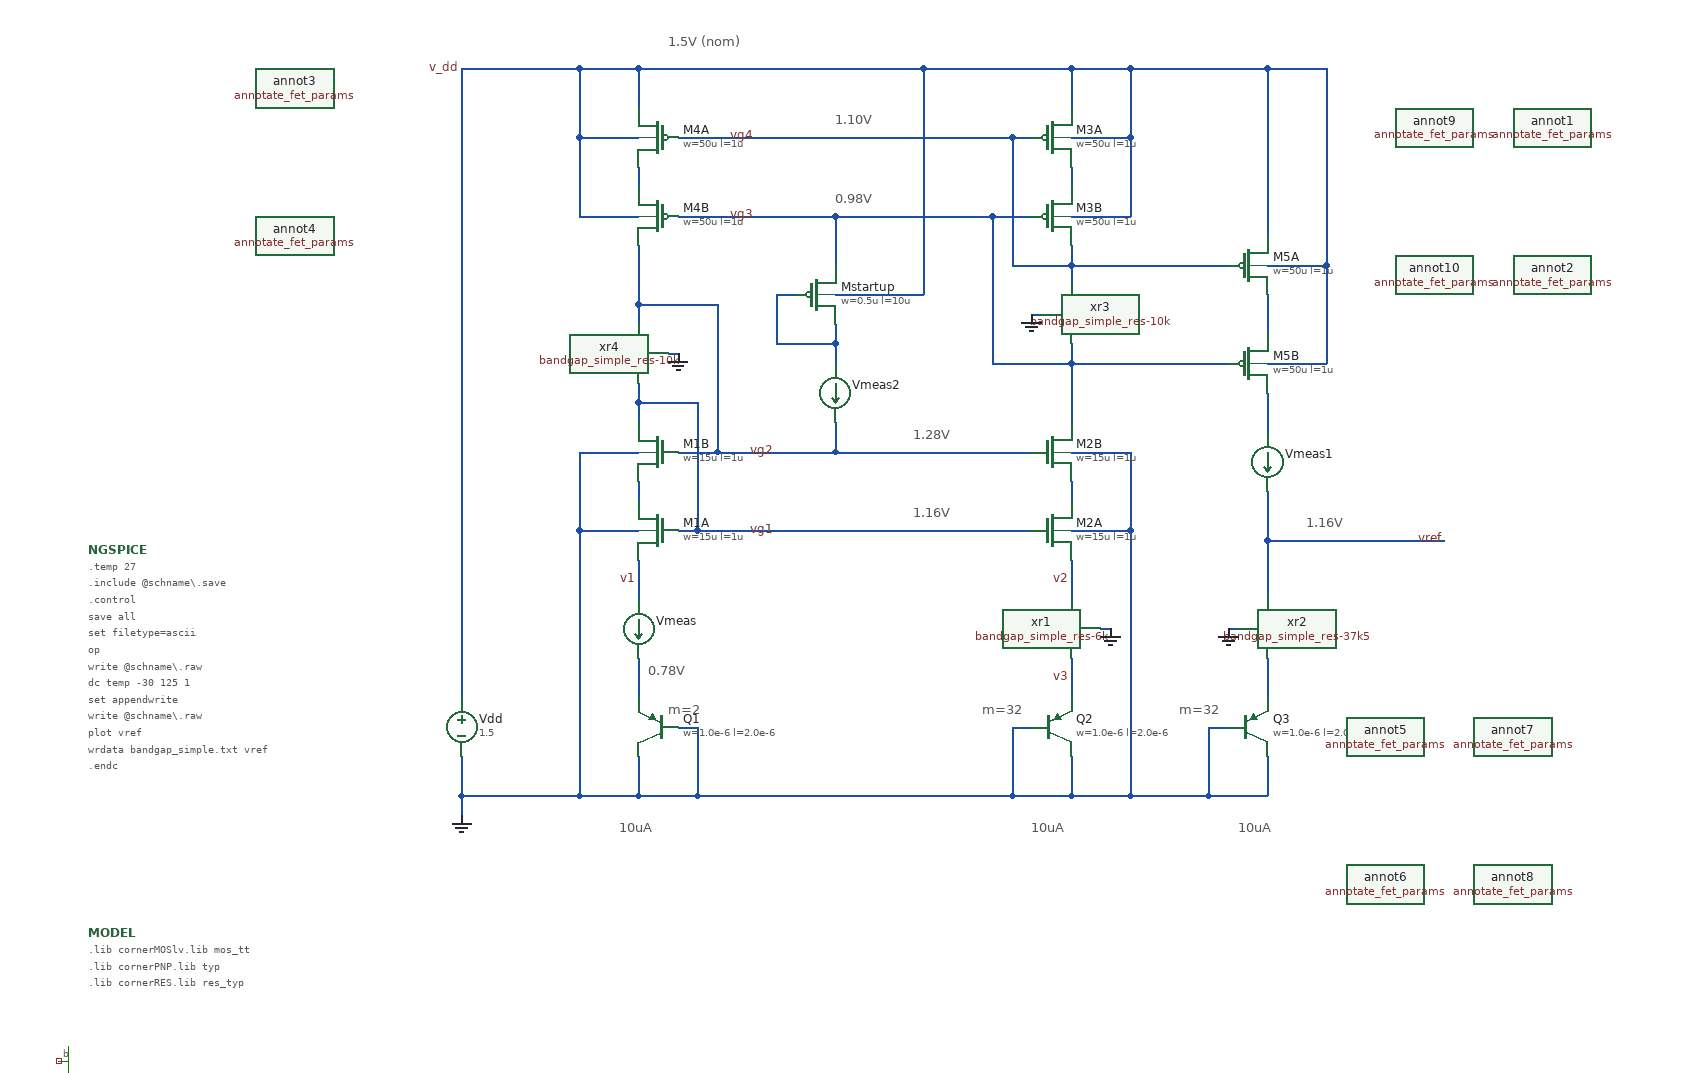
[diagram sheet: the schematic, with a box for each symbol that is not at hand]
v {xschem version=3.4.8RC file_version=1.3}
G {}
K {}
V {}
S {}
F {}
E {}
L 4 -20 -45 -20 -15 {}
L 4 -30 -30 -20 -30 {}
B 5 -32.5 -32.5 -27.5 -27.5 {name=b dir=inout}
T {m=32} 910 -400 0 0 0.4 0.4 {}
T {10uA} 540 -280 0 0 0.4 0.4 {}
T {10uA} 960 -280 0 0 0.4 0.4 {}
T {10uA} 1170 -280 0 0 0.4 0.4 {}
T {m=2} 590 -400 0 0 0.4 0.4 {}
T {m=32} 1110 -400 0 0 0.4 0.4 {}
T {1.16V} 1240 -590 0 0 0.4 0.4 {}
T {1.16V} 840 -600 0 0 0.4 0.4 {}
T {1.28V} 840 -680 0 0 0.4 0.4 {}
T {1.10V} 760 -1000 0 0 0.4 0.4 {}
T {0.98V} 760 -920 0 0 0.4 0.4 {}
T {0.78V} 570 -440 0 0 0.4 0.4 {}
T {1.5V (nom)} 590 -1080 0 0 0.4 0.4 {}
T {b} -25 -49 0 1 0.2 0.2 {}
N 380 -300 380 -280 {
lab=GND}
N 380 -340 380 -300 {
lab=GND}
N 1000 -340 1000 -300 {lab=GND}
N 560 -340 560 -300 {lab=GND}
N 940 -370 960 -370 {lab=GND}
N 940 -370 940 -300 {lab=GND}
N 600 -370 620 -370 {lab=GND}
N 620 -370 620 -300 {lab=GND}
N 560 -300 620 -300 {
lab=GND}
N 1000 -440 1000 -400 {lab=v3}
N 560 -1040 560 -1000 {lab=v_dd}
N 850 -1040 1000 -1040 {lab=v_dd}
N 1000 -1040 1000 -1000 {lab=v_dd}
N 500 -1040 560 -1040 {lab=v_dd}
N 940 -970 960 -970 {lab=vg4}
N 600 -570 620 -570 {lab=vg1}
N 500 -970 560 -970 {lab=v_dd}
N 500 -1040 500 -970 {lab=v_dd}
N 380 -1040 500 -1040 {lab=v_dd}
N 1000 -970 1060 -970 {lab=v_dd}
N 1060 -1040 1060 -970 {lab=v_dd}
N 1000 -1040 1060 -1040 {lab=v_dd}
N 500 -570 560 -570 {lab=GND}
N 500 -300 560 -300 {
lab=GND}
N 1000 -570 1060 -570 {lab=GND}
N 1060 -300 1140 -300 {lab=GND}
N 1140 -300 1200 -300 {
lab=GND}
N 1200 -340 1200 -300 {lab=GND}
N 1140 -370 1160 -370 {lab=GND}
N 1140 -370 1140 -300 {lab=GND}
N 1200 -440 1200 -400 {lab=#net1}
N 1060 -1040 1200 -1040 {lab=v_dd}
N 1200 -560 1200 -500 {lab=vref}
N 1200 -1040 1260 -1040 {lab=v_dd}
N 1200 -560 1380 -560 {lab=vref}
N 560 -440 560 -400 {lab=#net2}
N 1200 -610 1200 -560 {lab=vref}
N 1000 -620 1000 -600 {lab=#net3}
N 1000 -650 1060 -650 {lab=GND}
N 1060 -650 1060 -570 {lab=GND}
N 560 -620 560 -600 {lab=#net4}
N 500 -650 560 -650 {lab=GND}
N 500 -650 500 -570 {lab=GND}
N 560 -700 620 -700 {lab=vg1}
N 560 -700 560 -680 {lab=vg1}
N 560 -720 560 -700 {lab=vg1}
N 620 -700 620 -570 {lab=vg1}
N 640 -800 640 -650 {lab=vg2}
N 600 -650 640 -650 {lab=vg2}
N 560 -800 640 -800 {lab=vg2}
N 560 -800 560 -780 {lab=vg2}
N 560 -860 560 -800 {lab=vg2}
N 560 -940 560 -920 {lab=#net5}
N 920 -890 960 -890 {lab=vg3}
N 1000 -940 1000 -920 {lab=#net6}
N 1000 -890 1060 -890 {lab=v_dd}
N 1060 -970 1060 -890 {lab=v_dd}
N 500 -890 560 -890 {lab=v_dd}
N 500 -970 500 -890 {lab=v_dd}
N 940 -840 1000 -840 {lab=vg4}
N 920 -890 920 -740 {lab=vg3}
N 1000 -760 1000 -740 {lab=vg3}
N 1000 -740 1160 -740 {lab=vg3}
N 1000 -740 1000 -680 {lab=vg3}
N 940 -970 940 -840 {lab=vg4}
N 1000 -860 1000 -840 {lab=vg4}
N 1000 -840 1160 -840 {lab=vg4}
N 1000 -840 1000 -820 {lab=vg4}
N 380 -1040 380 -400 {lab=v_dd}
N 560 -540 560 -500 {lab=v1}
N 500 -570 500 -300 {lab=GND}
N 1000 -540 1000 -500 {lab=v2}
N 1060 -570 1060 -300 {lab=GND}
N 920 -740 1000 -740 {lab=vg3}
N 380 -300 500 -300 {
lab=GND}
N 1000 -300 1060 -300 {lab=GND}
N 1200 -1040 1200 -870 {lab=v_dd}
N 1260 -840 1260 -740 {lab=v_dd}
N 1200 -740 1260 -740 {lab=v_dd}
N 1200 -840 1260 -840 {lab=v_dd}
N 1260 -1040 1260 -840 {lab=v_dd}
N 1200 -810 1200 -770 {lab=#net7}
N 1200 -710 1200 -670 {lab=#net8}
N 940 -300 1000 -300 {lab=GND}
N 620 -300 940 -300 {
lab=GND}
N 600 -970 940 -970 {lab=vg4}
N 700 -810 720 -810 {lab=#net9}
N 760 -780 760 -760 {lab=#net9}
N 620 -570 960 -570 {lab=vg1}
N 760 -890 920 -890 {lab=vg3}
N 760 -890 760 -840 {lab=vg3}
N 600 -890 760 -890 {lab=vg3}
N 760 -810 850 -810 {lab=v_dd}
N 560 -1040 850 -1040 {lab=v_dd}
N 700 -760 760 -760 {lab=#net9}
N 700 -810 700 -760 {lab=#net9}
N 760 -650 960 -650 {lab=vg2}
N 760 -680 760 -650 {lab=vg2}
N 640 -650 760 -650 {lab=vg2}
N 850 -1040 850 -810 {lab=v_dd}
N 760 -760 760 -740 {lab=#net9}
N 590 -750 600 -750 {lab=GND}
N 960 -790 970 -790 {lab=GND}
N 1160 -470 1170 -470 {lab=GND}
N 1030 -470 1040 -470 {lab=GND}
C {devices/code_shown.sym} 0 -160 0 0 {name=MODEL only_toplevel=true
format="tcleval( @value )"
value="
.lib cornerMOSlv.lib mos_tt
.lib cornerPNP.lib typ
.lib cornerRES.lib res_typ
"}
C {devices/code_shown.sym} 0 -550 0 0 {name=NGSPICE only_toplevel=true 
value="
.temp 27
.include @schname\\\\.save
.control
save all
set filetype=ascii

op
write @schname\\\\.raw

dc temp -30 125 1
set appendwrite
write @schname\\\\.raw
plot vref

wrdata bandgap_simple.txt vref
.endc
"}
C {devices/vsource.sym} 380 -370 0 0 {name=Vdd value=1.5}
C {devices/gnd.sym} 380 -280 0 0 {name=l3 lab=GND}
C {devices/title.sym} 160 -30 0 0 {name=l5 author="(c) 2025 Harald Pretl, Apache-2.0 license"}
C {devices/launcher.sym} 500 -150 0 0 {name=h2
descr="simulate" 
tclcommand="xschem save; xschem netlist; file mkdir $netlist_dir; write_data [save_params] $netlist_dir/[file rootname [file tail [xschem get current_name]]].save; xschem simulate"
}
C {devices/launcher.sym} 740 -150 0 0 {name=h3
descr="annotate OP" 
tclcommand="set show_hidden_texts 1; xschem annotate_op"
}
C {devices/lab_pin.sym} 380 -1040 0 0 {name=p2 sig_type=std_logic lab=v_dd}
C {sg13cmos5l_pr/pnpMPA.sym} 580 -370 0 1 {name=Q1
model=pnpMPA
spiceprefix=X
w=1.0e-6
l=2.0e-6
m=2
}
C {sg13cmos5l_pr/pnpMPA.sym} 980 -370 0 0 {name=Q2
model=pnpMPA
spiceprefix=X
w=1.0e-6
l=2.0e-6
m=32
}
C {sg13cmos5l_pr/sg13_lv_nmos.sym} 580 -570 0 1 {name=M1A
l=1u
w=15u
ng=3
m=1
model=sg13_lv_nmos
spiceprefix=X
}
C {sg13cmos5l_pr/pnpMPA.sym} 1180 -370 0 0 {name=Q3
model=pnpMPA
spiceprefix=X
w=1.0e-6
l=2.0e-6
m=32
}
C {devices/lab_wire.sym} 1380 -560 0 0 {name=p1 sig_type=std_logic lab=vref}
C {devices/ammeter.sym} 560 -470 0 0 {name=Vmeas savecurrent=true spice_ignore=0}
C {devices/ammeter.sym} 1200 -640 0 0 {name=Vmeas1 savecurrent=true spice_ignore=0}
C {devices/lab_pin.sym} 1000 -520 0 0 {name=p3 sig_type=std_logic lab=v2}
C {devices/lab_pin.sym} 1000 -420 0 0 {name=p4 sig_type=std_logic lab=v3}
C {devices/lab_pin.sym} 560 -520 0 0 {name=p5 sig_type=std_logic lab=v1}
C {devices/lab_wire.sym} 680 -970 0 0 {name=p6 sig_type=std_logic lab=vg4}
C {sg13cmos5l_pr/sg13_lv_pmos.sym} 580 -890 0 1 {name=M4B
l=1u
w=50u
ng=10
m=1
model=sg13_lv_pmos
spiceprefix=X
}
C {devices/lab_wire.sym} 700 -570 0 0 {name=p7 sig_type=std_logic lab=vg1}
C {devices/lab_wire.sym} 700 -650 0 0 {name=p8 sig_type=std_logic lab=vg2}
C {devices/lab_wire.sym} 680 -890 0 0 {name=p9 sig_type=std_logic lab=vg3}
C {sg13cmos5l_pr/sg13_lv_nmos.sym} 580 -650 0 1 {name=M1B
l=1u
w=15u
ng=3
m=1
model=sg13_lv_nmos
spiceprefix=X
}
C {sg13cmos5l_pr/sg13_lv_nmos.sym} 980 -570 0 0 {name=M2A
l=1u
w=15u
ng=3
m=1
model=sg13_lv_nmos
spiceprefix=X
}
C {sg13cmos5l_pr/sg13_lv_nmos.sym} 980 -650 0 0 {name=M2B
l=1u
w=15u
ng=3
m=1
model=sg13_lv_nmos
spiceprefix=X
}
C {sg13cmos5l_pr/sg13_lv_pmos.sym} 580 -970 0 1 {name=M4A
l=1u
w=50u
ng=10
m=1
model=sg13_lv_pmos
spiceprefix=X
}
C {sg13cmos5l_pr/sg13_lv_pmos.sym} 980 -890 0 0 {name=M3B
l=1u
w=50u
ng=10
m=1
model=sg13_lv_pmos
spiceprefix=X
}
C {sg13cmos5l_pr/sg13_lv_pmos.sym} 980 -970 0 0 {name=M3A
l=1u
w=50u
ng=10
m=1
model=sg13_lv_pmos
spiceprefix=X
}
C {sg13cmos5l_pr/sg13_lv_pmos.sym} 1180 -840 0 0 {name=M5A
l=1u
w=50u
ng=10
m=1
model=sg13_lv_pmos
spiceprefix=X
}
C {sg13cmos5l_pr/sg13_lv_pmos.sym} 1180 -740 0 0 {name=M5B
l=1u
w=50u
ng=10
m=1
model=sg13_lv_pmos
spiceprefix=X
}
C {sg13cmos5l_pr/sg13_lv_pmos.sym} 740 -810 0 0 {name=Mstartup
l=10u
w=0.5u
ng=1
m=1
model=sg13_lv_pmos
spiceprefix=X
}
C {devices/ammeter.sym} 760 -710 0 0 {name=Vmeas2 savecurrent=true spice_ignore=0}
C {bandgap_simple_res-6k.sym} 1000 -440 0 1 {name=xr1}
C {bandgap_simple_res-10k.sym} 560 -720 0 1 {name=xr4}
C {bandgap_simple_res-10k.sym} 1000 -760 0 0 {name=xr3}
C {bandgap_simple_res-37k5.sym} 1200 -440 0 0 {name=xr2}
C {devices/gnd.sym} 600 -750 3 0 {name=l1 lab=GND}
C {devices/gnd.sym} 1040 -470 3 0 {name=l2 lab=GND}
C {devices/gnd.sym} 1160 -470 1 1 {name=l4 lab=GND}
C {devices/gnd.sym} 960 -790 1 1 {name=l6 lab=GND}
C {sg13cmos5l_pr/annotate_fet_params.sym} 1490 -980 0 0 {name=annot1 ref=M5A}
C {sg13cmos5l_pr/annotate_fet_params.sym} 1490 -830 0 0 {name=annot2 ref=M5B}
C {sg13cmos5l_pr/annotate_fet_params.sym} 210 -1020 0 0 {name=annot3 ref=M4A}
C {sg13cmos5l_pr/annotate_fet_params.sym} 210 -870 0 0 {name=annot4 ref=M4B}
C {sg13cmos5l_pr/annotate_fet_params.sym} 1320 -360 0 0 {name=annot5 ref=M1B}
C {sg13cmos5l_pr/annotate_fet_params.sym} 1320 -210 0 0 {name=annot6 ref=M1A}
C {sg13cmos5l_pr/annotate_fet_params.sym} 1450 -360 0 0 {name=annot7 ref=M2B}
C {sg13cmos5l_pr/annotate_fet_params.sym} 1450 -210 0 0 {name=annot8 ref=M2A}
C {sg13cmos5l_pr/annotate_fet_params.sym} 1370 -980 0 0 {name=annot9 ref=M3A}
C {sg13cmos5l_pr/annotate_fet_params.sym} 1370 -830 0 0 {name=annot10 ref=M3B}
